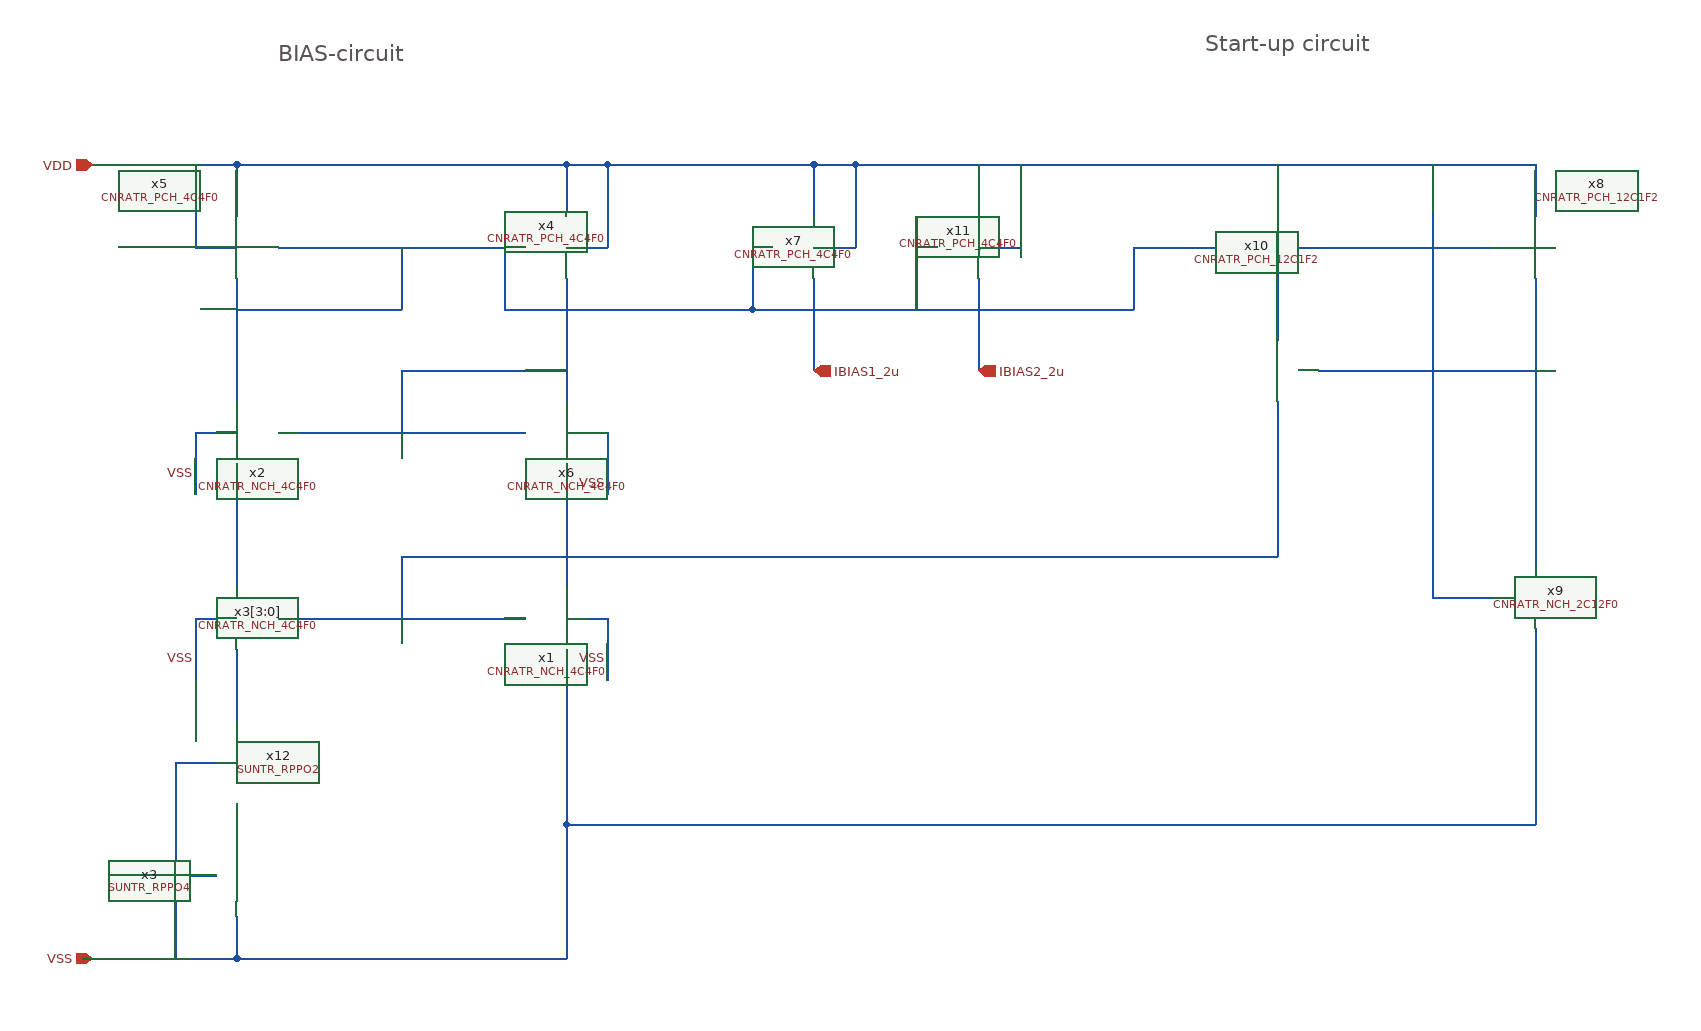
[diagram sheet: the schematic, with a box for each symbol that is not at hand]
v {xschem version=3.4.4 file_version=1.2
}
G {}
K {}
V {}
S {}
E {}
T {BIAS-circuit} 520 -820 0 0 0.8 0.8 {}
T {Start-up circuit} 1420 -830 0 0 0.8 0.8 {}
N 800 -590 800 -470 {
lab=#net1}
N 480 -590 480 -470 {
lab=#net2}
N 480 -410 480 -290 {
lab=#net3}
N 800 -410 800 -290 {
lab=#net4}
N 520 -620 760 -620 {
lab=#net2}
N 520 -440 760 -440 {
lab=#net1}
N 640 -500 640 -440 {
lab=#net1}
N 640 -500 800 -500 {
lab=#net1}
N 640 -620 640 -560 {
lab=#net2}
N 480 -560 640 -560 {
lab=#net2}
N 520 -260 760 -260 {
lab=#net4}
N 640 -320 800 -320 {
lab=#net4}
N 640 -320 640 -260 {
lab=#net4}
N 330 -700 480 -700 {
lab=VDD}
N 480 -700 480 -650 {
lab=VDD}
N 480 -700 800 -700 {
lab=VDD}
N 800 -700 800 -650 {
lab=VDD}
N 480 -230 480 -180 {
lab=#net5}
N 330 70 480 70 {
lab=VSS}
N 480 30 480 70 {
lab=VSS}
N 800 -230 800 -60 {
lab=VSS}
N 440 -10 460 -10 {
lab=VSS}
N 420 -10 440 -10 {
lab=VSS}
N 420 -10 420 70 {
lab=VSS}
N 440 -620 480 -620 {
lab=VDD}
N 440 -700 440 -620 {
lab=VDD}
N 800 -620 840 -620 {
lab=VDD}
N 840 -700 840 -620 {
lab=VDD}
N 800 -700 840 -700 {
lab=VDD}
N 440 -440 480 -440 {
lab=VSS}
N 440 -440 440 -380 {
lab=VSS}
N 800 -440 840 -440 {
lab=VSS}
N 840 -440 840 -380 {
lab=VSS}
N 440 -260 480 -260 {
lab=VSS}
N 440 -260 440 -200 {
lab=VSS}
N 800 -260 840 -260 {
lab=VSS}
N 840 -260 840 -200 {
lab=VSS}
N 840 -700 1040 -700 {
lab=VDD}
N 1040 -700 1080 -700 {
lab=VDD}
N 740 -620 740 -560 {
lab=#net2}
N 740 -560 980 -560 {
lab=#net2}
N 980 -620 980 -560 {
lab=#net2}
N 980 -620 1000 -620 {
lab=#net2}
N 1040 -700 1040 -650 {
lab=VDD}
N 1040 -620 1080 -620 {
lab=VDD}
N 1080 -700 1080 -620 {
lab=VDD}
N 800 -60 1040 -60 {
lab=VSS}
N 1740 -590 1740 -310 {
lab=#net6}
N 1600 -500 1740 -500 {
lab=#net6}
N 1740 -250 1740 -60 {
lab=VSS}
N 1050 -60 1740 -60 {
lab=VSS}
N 1040 -60 1050 -60 {
lab=VSS}
N 1080 -700 1740 -700 {
lab=VDD}
N 1740 -700 1740 -650 {
lab=VDD}
N 1680 -280 1700 -280 {
lab=VDD}
N 1660 -280 1680 -280 {
lab=VDD}
N 1640 -280 1660 -280 {
lab=VDD}
N 1640 -700 1640 -280 {
lab=VDD}
N 1530 -500 1600 -500 {
lab=#net6}
N 1490 -700 1490 -530 {
lab=VDD}
N 800 -320 1490 -320 {
lab=#net4}
N 1350 -620 1350 -560 {
lab=#net2}
N 980 -560 1280 -560 {
lab=#net2}
N 1490 -470 1490 -320 {
lab=#net4}
N 1350 -620 1700 -620 {
lab=#net2}
N 1280 -560 1350 -560 {
lab=#net2}
N 1200 -700 1200 -650 {
lab=VDD}
N 1200 -620 1240 -620 {
lab=VDD}
N 1240 -700 1240 -620 {
lab=VDD}
N 1140 -620 1160 -620 {
lab=#net2}
N 1140 -620 1140 -560 {
lab=#net2}
N 1040 -590 1040 -500 {
lab=IBIAS1_2u}
N 1200 -590 1200 -500 {
lab=IBIAS2_2u}
N 800 -60 800 70 {
lab=VSS}
N 480 70 800 70 {
lab=VSS}
N 480 -180 480 -160 {
lab=#net5}
N 480 -80 480 -50 {
lab=#net7}
N 420 -120 460 -120 {
lab=VSS}
N 420 -120 420 -10 {
lab=VSS}
C {CNR_ATR_SKY130NM/CNR_ATR_SKY130NM/CNRATR_PCH_4C4F0.sym} 760 -620 0 0 {name=x4}
C {CNR_ATR_SKY130NM/CNR_ATR_SKY130NM/CNRATR_PCH_4C4F0.sym} 520 -620 0 1 {name=x5}
C {CNR_ATR_SKY130NM/CNR_ATR_SKY130NM/CNRATR_NCH_4C4F0.sym} 760 -440 0 0 {name=x6 }
C {CNR_ATR_SKY130NM/CNR_ATR_SKY130NM/CNRATR_NCH_4C4F0.sym} 760 -260 0 0 {name=x1 }
C {CNR_ATR_SKY130NM/CNR_ATR_SKY130NM/CNRATR_NCH_4C4F0.sym} 520 -440 0 1 {name=x2 }
C {CNR_ATR_SKY130NM/CNR_ATR_SKY130NM/CNRATR_NCH_4C4F0.sym} 520 -260 0 1 {name=x3[3:0]}
C {devices/ipin.sym} 340 -700 0 0 {name=p1 lab=VDD}
C {devices/ipin.sym} 340 70 0 0 {name=p2 lab=VSS}
C {SUN_TR_SKY130NM/SUNTR_RPPO4.sym} 480 -50 1 0 {name=x3 }
C {CNR_ATR_SKY130NM/CNR_ATR_SKY130NM/CNRATR_PCH_4C4F0.sym} 1000 -620 0 0 {name=x7}
C {CNR_ATR_SKY130NM/CNR_ATR_SKY130NM/CNRATR_NCH_2C12F0.sym} 1700 -280 0 0 {name=x9 }
C {CNR_ATR_SKY130NM/CNR_ATR_SKY130NM/CNRATR_PCH_12C1F2.sym} 1700 -620 0 0 {name=x8 }
C {CNR_ATR_SKY130NM/CNR_ATR_SKY130NM/CNRATR_PCH_12C1F2.sym} 1530 -500 0 1 {name=x10 }
C {CNR_ATR_SKY130NM/CNR_ATR_SKY130NM/CNRATR_PCH_4C4F0.sym} 1160 -620 0 0 {name=x11}
C {devices/opin.sym} 1040 -500 0 0 {name=p3 lab=IBIAS1_2u}
C {devices/opin.sym} 1200 -500 0 0 {name=p4 lab=IBIAS2_2u}
C {devices/lab_wire.sym} 440 -220 0 0 {name=p6 sig_type=std_logic lab=VSS}
C {devices/lab_wire.sym} 840 -390 0 0 {name=p7 sig_type=std_logic lab=VSS}
C {devices/lab_wire.sym} 840 -220 0 0 {name=p8 sig_type=std_logic lab=VSS}
C {devices/lab_wire.sym} 440 -400 0 0 {name=p5 sig_type=std_logic lab=VSS}
C {SUN_TR_SKY130NM/SUNTR_RPPO2.sym} 480 -160 1 0 {name=x12 }
